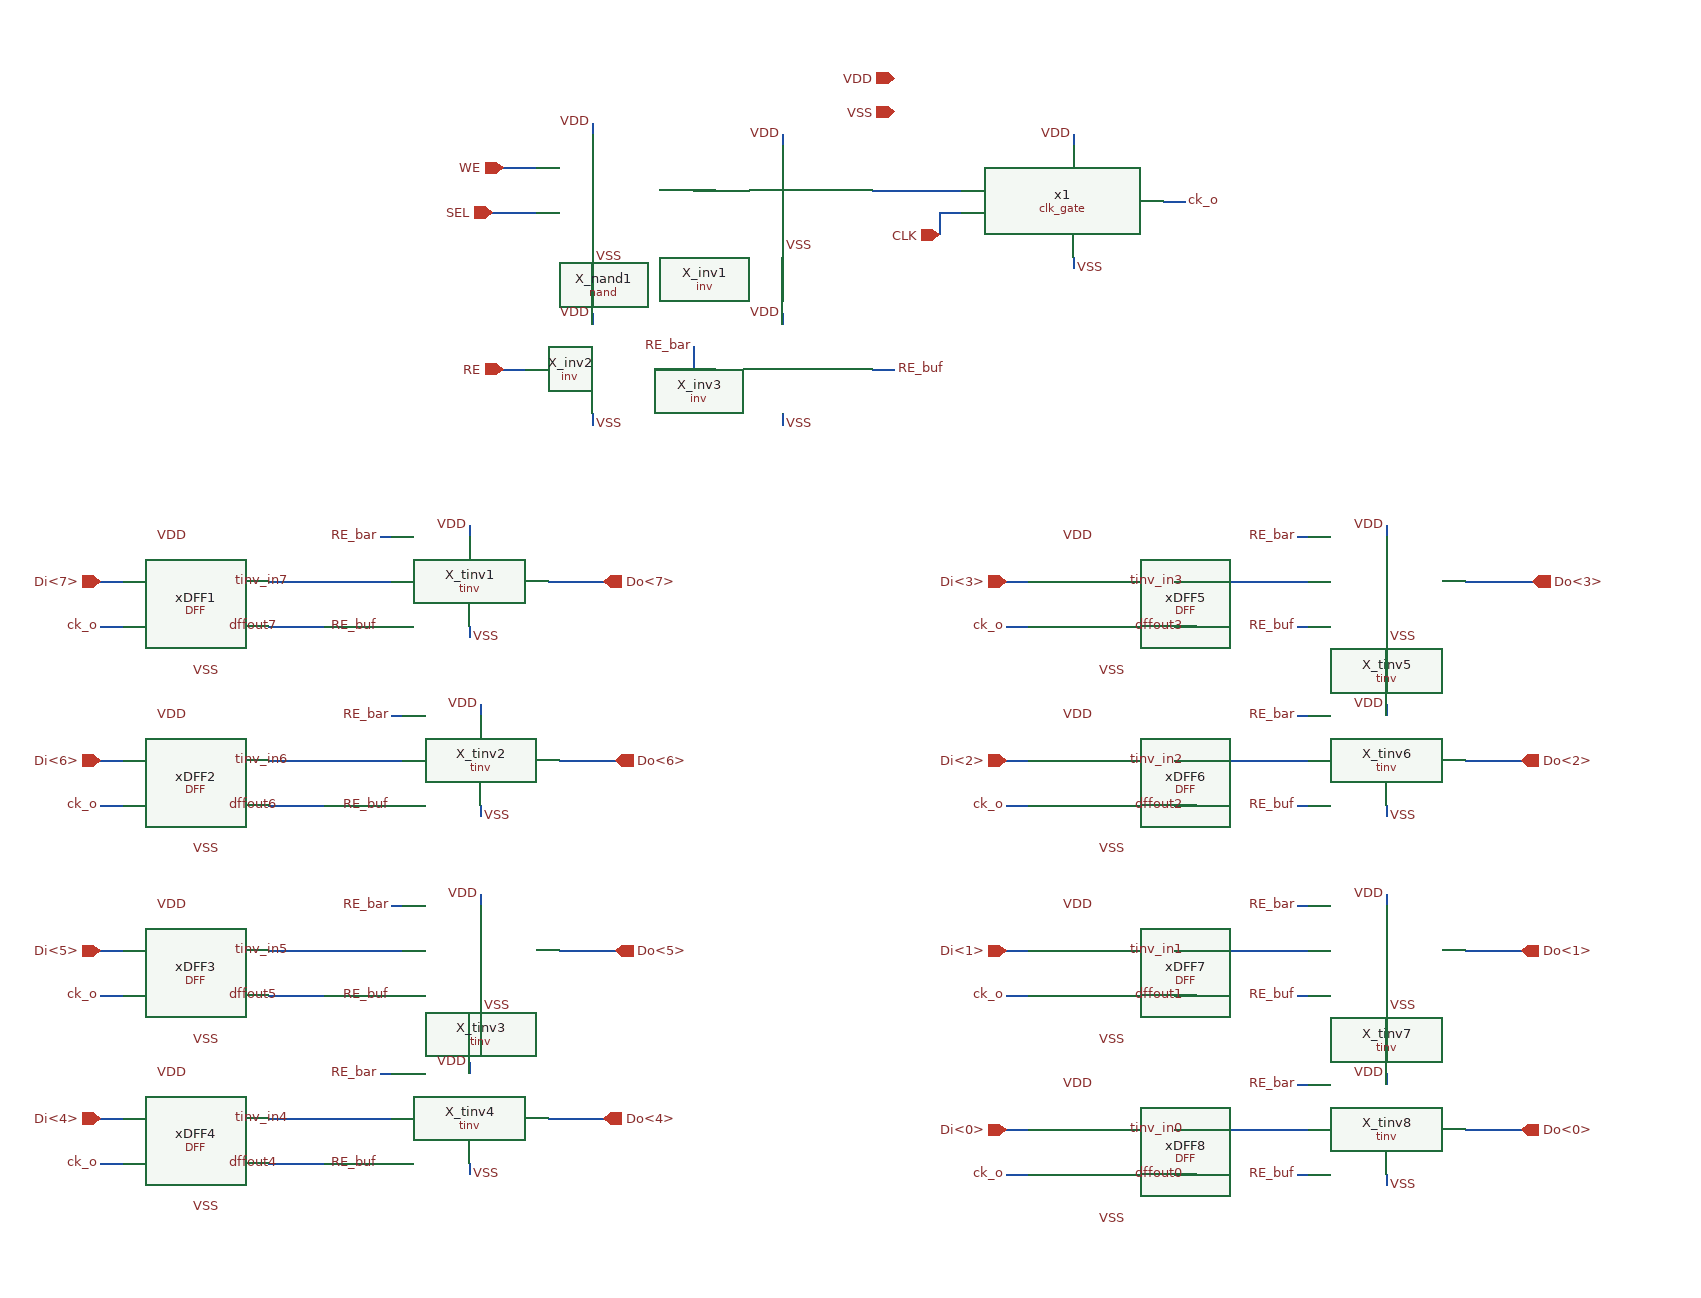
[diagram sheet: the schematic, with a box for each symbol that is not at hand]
v {xschem version=3.0.0 file_version=1.2 }
G {}
K {}
V {}
S {}
E {}
N 850 -160 880 -160 {
lab=Do<7>}
N 700 -120 710 -120 {
lab=RE_buf}
N 700 -160 710 -160 {
lab=tinv_in7}
N 700 -200 710 -200 {
lab=RE_bar}
N 690 -160 700 -160 {
lab=tinv_in7}
N 600 -120 620 -120 {
lab=dffout7}
N 780 -210 780 -200 {
lab=VDD}
N 780 -120 780 -110 {
lab=VSS}
N 880 -160 900 -160 {
lab=Do<7>}
N 450 -160 470 -160 {
lab=Di<7>}
N 460 -120 470 -120 {
lab=ck_o}
N 450 -120 460 -120 {
lab=ck_o}
N 600 40 620 40 {
lab=dffout6}
N 890 0 910 0 {
lab=Do<6>}
N 450 0 470 0 {
lab=Di<6>}
N 880 170 890 170 {
lab=Do<5>}
N 600 210 620 210 {
lab=dffout5}
N 890 170 910 170 {
lab=Do<5>}
N 450 170 470 170 {
lab=Di<5>}
N 600 360 620 360 {
lab=dffout4}
N 880 320 900 320 {
lab=Do<4>}
N 450 320 470 320 {
lab=Di<4>}
N 1700 -160 1710 -160 {
lab=Do<3>}
N 1710 -160 1730 -160 {
lab=Do<3>}
N 1260 -160 1280 -160 {
lab=Di<3>}
N 1690 0 1700 0 {
lab=Do<2>}
N 1410 40 1430 40 {
lab=dffout2}
N 1700 0 1720 0 {
lab=Do<2>}
N 1260 0 1280 0 {
lab=Di<2>}
N 1410 210 1430 210 {
lab=dffout1}
N 1700 170 1720 170 {
lab=Do<1>}
N 1260 170 1280 170 {
lab=Di<1>}
N 1690 330 1700 330 {
lab=Do<0>}
N 1410 370 1430 370 {
lab=dffout0}
N 1700 330 1720 330 {
lab=Do<0>}
N 1260 330 1280 330 {
lab=Di<0>}
N 810 -350 830 -350 {
lab=RE}
N 1140 -350 1160 -350 {
lab=RE_buf}
N 890 -400 890 -390 {
lab=VDD}
N 890 -310 890 -300 {
lab=VSS}
N 890 -570 890 -560 {
lab=VDD}
N 890 -460 890 -450 {
lab=VSS}
N 1060 -560 1060 -550 {
lab=VDD}
N 1060 -470 1060 -460 {
lab=VSS}
N 980 -510 1000 -510 {
lab=#net1}
N 810 -530 840 -530 {
lab=WE}
N 810 -490 840 -490 {
lab=SEL}
N 800 -490 810 -490 {
lab=SEL}
N 1140 -510 1220 -510 {
lab=#net2}
N 1200 -490 1220 -490 {
lab=CLK}
N 1200 -490 1200 -470 {
lab=CLK}
N 1320 -560 1320 -550 {
lab=VDD}
N 1320 -450 1320 -440 {
lab=VSS}
N 1400 -500 1420 -500 {
lab=ck_o}
N 860 0 890 0 {
lab=Do<6>}
N 710 40 720 40 {
lab=RE_buf}
N 710 0 720 0 {
lab=tinv_in6}
N 710 -40 720 -40 {
lab=RE_bar}
N 790 -50 790 -40 {
lab=VDD}
N 790 40 790 50 {
lab=VSS}
N 710 210 720 210 {
lab=RE_buf}
N 710 170 720 170 {
lab=tinv_in5}
N 710 130 720 130 {
lab=RE_bar}
N 790 120 790 130 {
lab=VDD}
N 790 210 790 220 {
lab=VSS}
N 850 320 880 320 {
lab=Do<4>}
N 700 360 710 360 {
lab=RE_buf}
N 700 320 710 320 {
lab=tinv_in4}
N 700 280 710 280 {
lab=RE_bar}
N 780 270 780 280 {
lab=VDD}
N 780 360 780 370 {
lab=VSS}
N 1670 -160 1700 -160 {
lab=Do<3>}
N 1520 -120 1530 -120 {
lab=RE_buf}
N 1520 -160 1530 -160 {
lab=tinv_in3}
N 1520 -200 1530 -200 {
lab=RE_bar}
N 1510 -160 1520 -160 {
lab=tinv_in3}
N 1600 -210 1600 -200 {
lab=VDD}
N 1600 -120 1600 -110 {
lab=VSS}
N 1520 40 1530 40 {
lab=RE_buf}
N 1520 0 1530 0 {
lab=tinv_in2}
N 1520 -40 1530 -40 {
lab=RE_bar}
N 1510 0 1520 0 {
lab=tinv_in2}
N 1600 -50 1600 -40 {
lab=VDD}
N 1600 40 1600 50 {
lab=VSS}
N 1670 170 1700 170 {
lab=Do<1>}
N 1520 210 1530 210 {
lab=RE_buf}
N 1520 170 1530 170 {
lab=tinv_in1}
N 1520 130 1530 130 {
lab=RE_bar}
N 1510 170 1520 170 {
lab=tinv_in1}
N 1600 120 1600 130 {
lab=VDD}
N 1600 210 1600 220 {
lab=VSS}
N 1520 370 1530 370 {
lab=RE_buf}
N 1520 330 1530 330 {
lab=tinv_in0}
N 1520 290 1530 290 {
lab=RE_bar}
N 1510 330 1520 330 {
lab=tinv_in0}
N 1600 280 1600 290 {
lab=VDD}
N 1600 370 1600 380 {
lab=VSS}
N 860 170 880 170 {
lab=Do<5>}
N 1670 330 1690 330 {
lab=Do<0>}
N 1670 0 1690 0 {
lab=Do<2>}
N 1410 -120 1430 -120 {
lab=dffout3}
N 460 40 470 40 {
lab=ck_o}
N 450 40 460 40 {
lab=ck_o}
N 460 210 470 210 {
lab=ck_o}
N 450 210 460 210 {
lab=ck_o}
N 460 360 470 360 {
lab=ck_o}
N 450 360 460 360 {
lab=ck_o}
N 1270 -120 1280 -120 {
lab=ck_o}
N 1260 -120 1270 -120 {
lab=ck_o}
N 1270 40 1280 40 {
lab=ck_o}
N 1260 40 1270 40 {
lab=ck_o}
N 1270 210 1280 210 {
lab=ck_o}
N 1260 210 1270 210 {
lab=ck_o}
N 1270 370 1280 370 {
lab=ck_o}
N 1260 370 1270 370 {
lab=ck_o}
N 1410 -160 1470 -160 {
lab=tinv_in3}
N 1410 0 1470 0 {
lab=tinv_in2}
N 1410 170 1470 170 {
lab=tinv_in1}
N 1410 330 1470 330 {
lab=tinv_in0}
N 970 -350 1000 -350 {
lab=RE_bar}
N 980 -370 980 -350 {
lab=RE_bar}
N 1060 -400 1060 -390 {
lab=VDD}
N 1060 -310 1060 -300 {
lab=VSS}
N 600 -160 620 -160 {
lab=tinv_in7}
N 620 -120 650 -120 {
lab=dffout7}
N 600 0 620 0 {
lab=tinv_in6}
N 620 40 650 40 {
lab=dffout6}
N 600 170 620 170 {
lab=tinv_in5}
N 620 210 650 210 {
lab=dffout5}
N 600 320 620 320 {
lab=tinv_in4}
N 620 360 650 360 {
lab=dffout4}
N 620 -160 640 -160 {
lab=tinv_in7}
N 620 0 640 0 {
lab=tinv_in6}
N 620 170 640 170 {
lab=tinv_in5}
N 620 320 640 320 {
lab=tinv_in4}
N 650 320 700 320 {
lab=tinv_in4}
N 640 320 650 320 {
lab=tinv_in4}
N 640 170 710 170 {
lab=tinv_in5}
N 640 0 710 0 {
lab=tinv_in6}
N 640 -160 690 -160 {
lab=tinv_in7}
N 1470 -160 1510 -160 {
lab=tinv_in3}
N 1470 -0 1510 0 {
lab=tinv_in2}
N 1470 170 1510 170 {
lab=tinv_in1}
N 1470 330 1510 330 {
lab=tinv_in0}
C {xschem_lib/DFFRAM_full_custom/nand.sym} 860 -480 0 0 {name=X_nand1 NF=1}
C {xschem_lib/DFFRAM_full_custom/inv.sym} 1000 -470 0 0 {name=X_inv1 NF=2}
C {xschem_lib/DFFRAM_full_custom/inv.sym} 830 -310 0 0 {name=X_inv2 NF=NF*3}
C {xschem_lib/DFFRAM_full_custom/clk_gate.sym} 1320 -500 0 0 {name=x1 NF=2}
C {xschem_lib/DFFRAM_full_custom/DFF.sym} 530 -140 0 0 {name=xDFF1 NF=1}
C {xschem_lib/DFFRAM_full_custom/tinv.sym} 710 -120 0 0 {name=X_tinv1 NF=NF}
C {lab_wire.sym} 530 -200 0 0 {name=l3 sig_type=std_logic lab=VDD}
C {lab_wire.sym} 530 -80 2 0 {name=l4 sig_type=std_logic lab=VSS}
C {lab_wire.sym} 780 -210 0 0 {name=l5 sig_type=std_logic lab=VDD}
C {lab_wire.sym} 780 -110 2 0 {name=l7 sig_type=std_logic lab=VSS}
C {opin.sym} 900 -160 0 0 {name=p1 lab=Do<7>}
C {ipin.sym} 450 -160 0 0 {name=p2 lab=Di<7>}
C {lab_wire.sym} 450 -120 0 0 {name=l9 sig_type=std_logic lab=ck_o}
C {xschem_lib/DFFRAM_full_custom/DFF.sym} 530 20 0 0 {name=xDFF2 NF=1}
C {lab_wire.sym} 530 -40 0 0 {name=l12 sig_type=std_logic lab=VDD}
C {lab_wire.sym} 530 80 2 0 {name=l13 sig_type=std_logic lab=VSS}
C {opin.sym} 910 0 0 0 {name=p3 lab=Do<6>}
C {ipin.sym} 450 0 0 0 {name=p4 lab=Di<6>}
C {xschem_lib/DFFRAM_full_custom/DFF.sym} 530 190 0 0 {name=xDFF3 NF=1}
C {lab_wire.sym} 530 130 0 0 {name=l21 sig_type=std_logic lab=VDD}
C {lab_wire.sym} 530 250 2 0 {name=l22 sig_type=std_logic lab=VSS}
C {opin.sym} 910 170 0 0 {name=p5 lab=Do<5>}
C {ipin.sym} 450 170 0 0 {name=p6 lab=Di<5>}
C {xschem_lib/DFFRAM_full_custom/DFF.sym} 530 340 0 0 {name=xDFF4 NF=1}
C {lab_wire.sym} 530 280 0 0 {name=l30 sig_type=std_logic lab=VDD}
C {lab_wire.sym} 530 400 2 0 {name=l31 sig_type=std_logic lab=VSS}
C {opin.sym} 900 320 0 0 {name=p7 lab=Do<4>}
C {ipin.sym} 450 320 0 0 {name=p8 lab=Di<4>}
C {xschem_lib/DFFRAM_full_custom/DFF.sym} 1340 -140 0 0 {name=xDFF5 NF=1}
C {lab_wire.sym} 1340 -200 0 0 {name=l39 sig_type=std_logic lab=VDD}
C {lab_wire.sym} 1340 -80 2 0 {name=l40 sig_type=std_logic lab=VSS}
C {opin.sym} 1730 -160 0 0 {name=p9 lab=Do<3>}
C {ipin.sym} 1260 -160 0 0 {name=p10 lab=Di<3>}
C {xschem_lib/DFFRAM_full_custom/DFF.sym} 1340 20 0 0 {name=xDFF6 NF=1}
C {lab_wire.sym} 1340 -40 0 0 {name=l48 sig_type=std_logic lab=VDD}
C {lab_wire.sym} 1340 80 2 0 {name=l49 sig_type=std_logic lab=VSS}
C {opin.sym} 1720 0 0 0 {name=p11 lab=Do<2>}
C {ipin.sym} 1260 0 0 0 {name=p12 lab=Di<2>}
C {xschem_lib/DFFRAM_full_custom/DFF.sym} 1340 190 0 0 {name=xDFF7 NF=1}
C {lab_wire.sym} 1340 130 0 0 {name=l57 sig_type=std_logic lab=VDD}
C {lab_wire.sym} 1340 250 2 0 {name=l58 sig_type=std_logic lab=VSS}
C {opin.sym} 1720 170 0 0 {name=p13 lab=Do<1>}
C {ipin.sym} 1260 170 0 0 {name=p14 lab=Di<1>}
C {xschem_lib/DFFRAM_full_custom/DFF.sym} 1340 350 0 0 {name=xDFF8 NF=1}
C {lab_wire.sym} 1340 290 0 0 {name=l66 sig_type=std_logic lab=VDD}
C {lab_wire.sym} 1340 410 2 0 {name=l67 sig_type=std_logic lab=VSS}
C {opin.sym} 1720 330 0 0 {name=p15 lab=Do<0>}
C {ipin.sym} 1260 330 0 0 {name=p16 lab=Di<0>}
C {lab_wire.sym} 1160 -350 2 0 {name=l73 sig_type=std_logic lab=RE_buf}
C {lab_wire.sym} 890 -400 0 0 {name=l74 sig_type=std_logic lab=VDD}
C {lab_wire.sym} 890 -300 2 0 {name=l75 sig_type=std_logic lab=VSS}
C {lab_wire.sym} 890 -570 0 0 {name=l76 sig_type=std_logic lab=VDD}
C {lab_wire.sym} 890 -450 2 0 {name=l77 sig_type=std_logic lab=VSS}
C {lab_wire.sym} 1060 -560 0 0 {name=l78 sig_type=std_logic lab=VDD}
C {lab_wire.sym} 1060 -460 2 0 {name=l79 sig_type=std_logic lab=VSS}
C {ipin.sym} 810 -530 0 0 {name=p18 lab=WE}
C {ipin.sym} 800 -490 0 0 {name=p19 lab=SEL}
C {ipin.sym} 1200 -470 3 0 {name=p17 lab=CLK}
C {lab_wire.sym} 1320 -560 0 0 {name=l80 sig_type=std_logic lab=VDD}
C {lab_wire.sym} 1320 -440 2 0 {name=l81 sig_type=std_logic lab=VSS}
C {lab_wire.sym} 1420 -500 2 0 {name=l82 sig_type=std_logic lab=ck_o}
C {iopin.sym} 1160 -610 0 0 {name=p20 lab=VDD}
C {iopin.sym} 1160 -580 0 0 {name=p21 lab=VSS}
C {xschem_lib/DFFRAM_full_custom/tinv.sym} 720 40 0 0 {name=X_tinv2 NF=NF}
C {lab_wire.sym} 790 -50 0 0 {name=l14 sig_type=std_logic lab=VDD}
C {lab_wire.sym} 790 50 2 0 {name=l16 sig_type=std_logic lab=VSS}
C {xschem_lib/DFFRAM_full_custom/tinv.sym} 720 210 0 0 {name=X_tinv3 NF=NF}
C {lab_wire.sym} 790 120 0 0 {name=l23 sig_type=std_logic lab=VDD}
C {lab_wire.sym} 790 220 2 0 {name=l25 sig_type=std_logic lab=VSS}
C {xschem_lib/DFFRAM_full_custom/tinv.sym} 710 360 0 0 {name=X_tinv4 NF=NF}
C {lab_wire.sym} 780 270 0 0 {name=l32 sig_type=std_logic lab=VDD}
C {lab_wire.sym} 780 370 2 0 {name=l34 sig_type=std_logic lab=VSS}
C {xschem_lib/DFFRAM_full_custom/tinv.sym} 1530 -120 0 0 {name=X_tinv5 NF=NF}
C {lab_wire.sym} 1600 -210 0 0 {name=l41 sig_type=std_logic lab=VDD}
C {lab_wire.sym} 1600 -110 2 0 {name=l43 sig_type=std_logic lab=VSS}
C {xschem_lib/DFFRAM_full_custom/tinv.sym} 1530 40 0 0 {name=X_tinv6 NF=NF}
C {lab_wire.sym} 1600 -50 0 0 {name=l50 sig_type=std_logic lab=VDD}
C {lab_wire.sym} 1600 50 2 0 {name=l52 sig_type=std_logic lab=VSS}
C {xschem_lib/DFFRAM_full_custom/tinv.sym} 1530 210 0 0 {name=X_tinv7 NF=NF}
C {lab_wire.sym} 1600 120 0 0 {name=l59 sig_type=std_logic lab=VDD}
C {lab_wire.sym} 1600 220 2 0 {name=l61 sig_type=std_logic lab=VSS}
C {xschem_lib/DFFRAM_full_custom/tinv.sym} 1530 370 0 0 {name=X_tinv8 NF=NF}
C {lab_wire.sym} 1600 280 0 0 {name=l68 sig_type=std_logic lab=VDD}
C {lab_wire.sym} 1600 380 2 0 {name=l70 sig_type=std_logic lab=VSS}
C {lab_pin.sym} 1420 370 1 0 {name=l83 sig_type=std_logic lab=dffout0}
C {lab_pin.sym} 1420 210 1 0 {name=l84 sig_type=std_logic lab=dffout1}
C {lab_pin.sym} 1420 40 1 0 {name=l85 sig_type=std_logic lab=dffout2}
C {lab_pin.sym} 1420 -120 1 0 {name=l86 sig_type=std_logic lab=dffout3}
C {lab_pin.sym} 610 360 1 0 {name=l87 sig_type=std_logic lab=dffout4}
C {lab_pin.sym} 610 210 1 0 {name=l88 sig_type=std_logic lab=dffout5}
C {lab_pin.sym} 610 40 1 0 {name=l89 sig_type=std_logic lab=dffout6}
C {lab_pin.sym} 610 -120 1 0 {name=l90 sig_type=std_logic lab=dffout7}
C {lab_wire.sym} 450 40 0 0 {name=l18 sig_type=std_logic lab=ck_o}
C {lab_wire.sym} 450 210 0 0 {name=l27 sig_type=std_logic lab=ck_o}
C {lab_wire.sym} 450 360 0 0 {name=l36 sig_type=std_logic lab=ck_o}
C {lab_wire.sym} 1260 -120 0 0 {name=l6 sig_type=std_logic lab=ck_o}
C {lab_wire.sym} 1260 40 0 0 {name=l8 sig_type=std_logic lab=ck_o}
C {lab_wire.sym} 1260 210 0 0 {name=l15 sig_type=std_logic lab=ck_o}
C {lab_wire.sym} 1260 370 0 0 {name=l17 sig_type=std_logic lab=ck_o}
C {xschem_lib/DFFRAM_full_custom/inv.sym} 1000 -310 0 0 {name=X_inv3 NF=NF*3}
C {lab_wire.sym} 980 -370 1 0 {name=l24 sig_type=std_logic lab=RE_bar}
C {lab_wire.sym} 1060 -400 0 0 {name=l26 sig_type=std_logic lab=VDD}
C {lab_wire.sym} 1060 -300 2 0 {name=l33 sig_type=std_logic lab=VSS}
C {lab_pin.sym} 1420 -160 1 0 {name=l62 sig_type=std_logic lab=tinv_in3}
C {lab_pin.sym} 1420 0 1 0 {name=l63 sig_type=std_logic lab=tinv_in2}
C {lab_pin.sym} 1420 170 1 0 {name=l69 sig_type=std_logic lab=tinv_in1}
C {lab_pin.sym} 1420 330 1 0 {name=l71 sig_type=std_logic lab=tinv_in0}
C {lab_pin.sym} 620 -160 1 0 {name=l98 sig_type=std_logic lab=tinv_in7}
C {lab_pin.sym} 620 0 1 0 {name=l99 sig_type=std_logic lab=tinv_in6}
C {lab_pin.sym} 620 170 1 0 {name=l100 sig_type=std_logic lab=tinv_in5}
C {lab_pin.sym} 620 320 1 0 {name=l101 sig_type=std_logic lab=tinv_in4}
C {ipin.sym} 810 -350 0 0 {name=p22 lab=RE}
C {lab_wire.sym} 700 -200 0 0 {name=l2 sig_type=std_logic lab=RE_bar}
C {lab_wire.sym} 710 -40 0 0 {name=l11 sig_type=std_logic lab=RE_bar}
C {lab_wire.sym} 710 130 0 0 {name=l20 sig_type=std_logic lab=RE_bar}
C {lab_wire.sym} 700 280 0 0 {name=l29 sig_type=std_logic lab=RE_bar}
C {lab_wire.sym} 1520 290 0 0 {name=l35 sig_type=std_logic lab=RE_bar}
C {lab_wire.sym} 1520 130 0 0 {name=l38 sig_type=std_logic lab=RE_bar}
C {lab_wire.sym} 1520 -40 0 0 {name=l42 sig_type=std_logic lab=RE_bar}
C {lab_wire.sym} 1520 -200 0 0 {name=l44 sig_type=std_logic lab=RE_bar}
C {lab_wire.sym} 710 40 0 0 {name=l1 sig_type=std_logic lab=RE_buf}
C {lab_wire.sym} 700 -120 0 0 {name=l10 sig_type=std_logic lab=RE_buf}
C {lab_wire.sym} 710 210 0 0 {name=l19 sig_type=std_logic lab=RE_buf}
C {lab_wire.sym} 700 360 0 0 {name=l28 sig_type=std_logic lab=RE_buf}
C {lab_wire.sym} 1520 370 0 0 {name=l37 sig_type=std_logic lab=RE_buf}
C {lab_wire.sym} 1520 210 0 0 {name=l45 sig_type=std_logic lab=RE_buf}
C {lab_wire.sym} 1520 40 0 0 {name=l46 sig_type=std_logic lab=RE_buf}
C {lab_wire.sym} 1520 -120 0 0 {name=l47 sig_type=std_logic lab=RE_buf}
